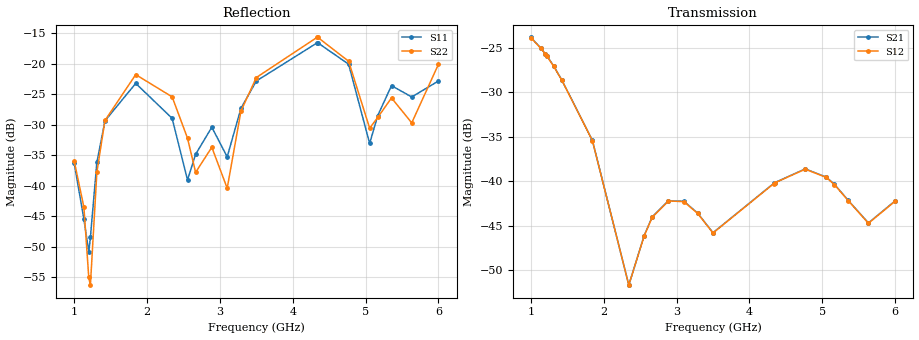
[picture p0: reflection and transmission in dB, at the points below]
!Agilent Technologies,E8364B,MY43040528,A.07.50.67
!Agilent E8364B: A.07.50.67
!Date: Sunday, March 01, 2026 22:07:04
!Correction: S11(Full 2 Port(1,2))
!S21(Full 2 Port(1,2))
!S12(Full 2 Port(1,2))
!S22(Full 2 Port(1,2))
!S2P File: Measurements: S11, S21, S12, S22:
# Hz S  dB  R 50
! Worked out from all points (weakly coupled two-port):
!   451 points, 1 GHz to 6 GHz, reference 50 ohm
!   highest |S21| = -23.86 dB at 1 GHz (marker M1); lowest = -51.7 dB at 2.344 GHz (marker M2)
!   lowest |S11| = -50.9 dB at 1.2 GHz (marker M3), VSWR 1.01, Z = 50.1 - j0.254 ohm
!   |S11| at or under -10 dB: start of sweep to end of sweep
!   |S22| runs from -58.3 to -15.7 dB; largest |S21 - S12| = 0.00026
!   S11 on the Smith chart (normalised r, x): 1 GHz: 1.03, +0.01; 4.333 GHz: 1.23, -0.24; 6 GHz: 0.98, -0.14
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1e9  -36.33 16.3  -23.86 154.8  -23.90 154.9  -35.96 -31.9
1.133333e9  -45.49 -2.7  -25.03 78.8  -25.06 78.8  -43.53 -25.5
1.2e9  -50.87 -62.2  -25.71 40.9  -25.74 40.9  -55.05 16.1
1.222222e9  -48.49 -101.2  -25.96 28.3  -25.99 28.4  -56.30 101.7
1.311111e9  -36.19 -149.9  -27.05 -21.7  -27.08 -21.7  -37.80 126.4
1.422222e9  -29.37 177.9  -28.60 -83.1  -28.63 -83.1  -29.31 98.2
1.844444e9  -23.23 83.2  -35.42 51.4  -35.44 51.5  -21.79 -11.0
2.344444e9  -28.96 13.1  -51.66 -148.5  -51.67 -148.6  -25.44 -113.7
2.555556e9  -39.06 28.4  -46.10 157.0  -46.14 157.2  -32.22 -148.6
2.666667e9  -34.85 71.1  -44.00 103.7  -44.05 103.8  -37.82 -129.1
2.888889e9  -30.41 47.1  -42.19 -10.8  -42.22 -10.9  -33.70 -118.4
3.1e9  -35.28 60.2  -42.25 -121.5  -42.30 -121.3  -40.42 -96.9
3.288889e9  -27.32 84.5  -43.58 142.9  -43.62 142.9  -27.77 -78.0
3.5e9  -22.84 55.0  -45.79 46.5  -45.82 46.7  -22.27 -121.9
4.333333e9  -16.60 -39.2  -40.25 29.4  -40.28 29.5  -15.69 102.5
4.344444e9  -16.59 -40.9  -40.18 23.4  -40.20 23.4  -15.70 100.3
4.766667e9  -20.08 -110.4  -38.62 148.5  -38.66 148.6  -19.60 15.5
5.055556e9  -33.08 -103.1  -39.55 -20.9  -39.58 -20.9  -30.57 3.6
5.166667e9  -28.50 -61.6  -40.35 -87.8  -40.39 -87.8  -28.81 29.4
5.355556e9  -23.60 -80.6  -42.15 154.0  -42.18 154.1  -25.61 9.0
5.633333e9  -25.46 -103.7  -44.69 -38.8  -44.73 -38.8  -29.70 5.0
6e9  -22.84 -94.8  -42.21 59.4  -42.25 59.4  -20.10 -19.3
